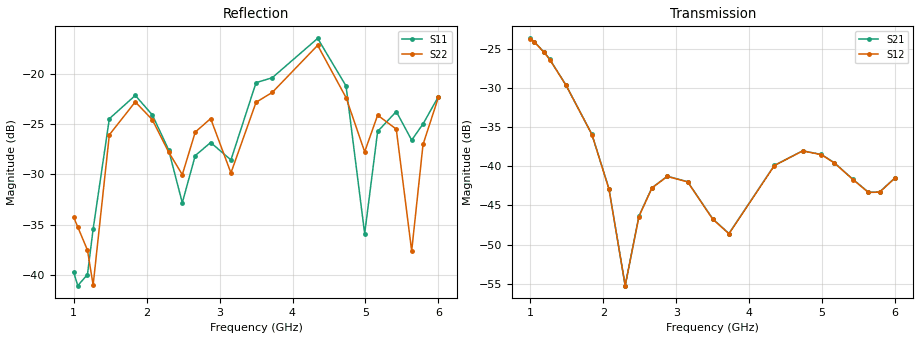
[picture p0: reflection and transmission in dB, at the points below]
!Agilent Technologies,E8364B,MY43040528,A.07.50.67
!Agilent E8364B: A.07.50.67
!Date: Sunday, March 01, 2026 20:44:05
!Correction: S11(Full 2 Port(1,2))
!S21(Full 2 Port(1,2))
!S12(Full 2 Port(1,2))
!S22(Full 2 Port(1,2))
!S2P File: Measurements: S11, S21, S12, S22:
# Hz S  dB  R 50
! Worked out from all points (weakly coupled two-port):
!   451 points, 1 GHz to 6 GHz, reference 50 ohm
!   highest |S21| = -23.64 dB at 1 GHz (marker M1); lowest = -55.3 dB at 2.3 GHz (marker M2)
!   lowest |S11| = -41.0 dB at 1.056 GHz (marker M3), VSWR 1.02, Z = 49.8 + j0.854 ohm
!   |S11| at or under -10 dB: start of sweep to end of sweep
!   |S22| runs from -41.1 to -16.9 dB; largest |S21 - S12| = 0.0002
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1e9  -39.70 77.6  -23.64 148.8  -23.66 148.7  -34.25 22.6
1.055556e9  -41.05 104.6  -24.10 116.5  -24.12 116.6  -35.21 26.0
1.188889e9  -39.94 148.0  -25.40 39.6  -25.43 39.5  -37.52 31.8
1.266667e9  -35.42 177.7  -26.33 -5.2  -26.36 -5.2  -40.99 76.0
1.488889e9  -24.46 155.2  -29.62 -129.5  -29.63 -129.6  -26.06 80.4
1.844444e9  -22.15 92.6  -35.92 38.0  -35.94 38.0  -22.79 2.3
2.077778e9  -24.08 65.2  -42.86 -85.0  -42.91 -85.0  -24.56 -33.3
2.3e9  -27.53 46.0  -55.25 -132.0  -55.24 -131.8  -27.75 -57.9
2.488889e9  -32.81 65.2  -46.34 -171.8  -46.41 -171.7  -30.02 -46.5
2.666667e9  -28.12 84.5  -42.74 96.5  -42.76 96.5  -25.79 -51.6
2.877778e9  -26.83 58.7  -41.26 -17.1  -41.29 -17.1  -24.45 -92.5
3.155556e9  -28.56 85.7  -41.96 -167.8  -41.98 -167.8  -29.85 -103.2
3.5e9  -20.88 54.6  -46.70 23.4  -46.75 23.2  -22.83 -122.1
3.722222e9  -20.39 35.6  -48.58 -52.5  -48.61 -52.5  -21.85 -144.6
4.344444e9  -16.48 -38.8  -39.88 13.0  -39.90 13.0  -17.17 113.3
4.733333e9  -21.21 -101.8  -38.01 152.5  -38.02 152.5  -22.36 42.0
4.988889e9  -35.88 -77.3  -38.48 1.3  -38.50 1.3  -27.75 49.9
5.166667e9  -25.73 -41.1  -39.53 -106.2  -39.56 -106.2  -24.11 40.8
5.422222e9  -23.75 -79.8  -41.66 91.0  -41.68 91.0  -25.50 -15.1
5.633333e9  -26.59 -82.2  -43.29 -56.9  -43.33 -57.0  -37.60 8.1
5.788889e9  -24.98 -71.8  -43.25 -170.8  -43.30 -170.7  -27.02 36.8
6e9  -22.26 -82.9  -41.46 42.2  -41.47 42.2  -22.33 -2.3
